VERSION 5.7 ;
  NOWIREEXTENSIONATPIN ON ;
  DIVIDERCHAR "/" ;
  BUSBITCHARS "[]" ;
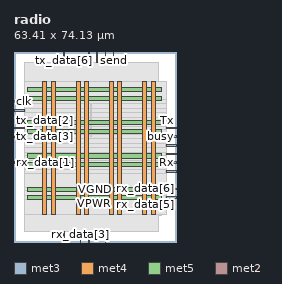
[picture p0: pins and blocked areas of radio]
MACRO radio
  CLASS BLOCK ;
  FOREIGN radio ;
  ORIGIN 0.000 0.000 ;
  SIZE 63.410 BY 74.130 ;
  PIN Rx
    DIRECTION INPUT ;
    USE SIGNAL ;
    ANTENNAGATEAREA 0.196500 ;
    PORT
      LAYER met3 ;
        RECT 59.410 30.640 63.410 31.240 ;
    END
  END Rx
  PIN Tx
    DIRECTION OUTPUT ;
    USE SIGNAL ;
    ANTENNADIFFAREA 0.340600 ;
    PORT
      LAYER met3 ;
        RECT 59.410 44.240 63.410 44.840 ;
    END
  END Tx
  PIN VGND
    DIRECTION INOUT ;
    USE GROUND ;
    PORT
      LAYER met4 ;
        RECT 14.515 10.640 16.115 62.800 ;
    END
    PORT
      LAYER met4 ;
        RECT 27.510 10.640 29.110 62.800 ;
    END
    PORT
      LAYER met4 ;
        RECT 40.505 10.640 42.105 62.800 ;
    END
    PORT
      LAYER met4 ;
        RECT 53.500 10.640 55.100 62.800 ;
    END
    PORT
      LAYER met5 ;
        RECT 5.280 19.840 57.740 21.440 ;
    END
    PORT
      LAYER met5 ;
        RECT 5.280 32.760 57.740 34.360 ;
    END
    PORT
      LAYER met5 ;
        RECT 5.280 45.680 57.740 47.280 ;
    END
    PORT
      LAYER met5 ;
        RECT 5.280 58.600 57.740 60.200 ;
    END
  END VGND
  PIN VPWR
    DIRECTION INOUT ;
    USE POWER ;
    PORT
      LAYER met4 ;
        RECT 11.215 10.640 12.815 62.800 ;
    END
    PORT
      LAYER met4 ;
        RECT 24.210 10.640 25.810 62.800 ;
    END
    PORT
      LAYER met4 ;
        RECT 37.205 10.640 38.805 62.800 ;
    END
    PORT
      LAYER met4 ;
        RECT 50.200 10.640 51.800 62.800 ;
    END
    PORT
      LAYER met5 ;
        RECT 5.280 16.540 57.740 18.140 ;
    END
    PORT
      LAYER met5 ;
        RECT 5.280 29.460 57.740 31.060 ;
    END
    PORT
      LAYER met5 ;
        RECT 5.280 42.380 57.740 43.980 ;
    END
    PORT
      LAYER met5 ;
        RECT 5.280 55.300 57.740 56.900 ;
    END
  END VPWR
  PIN busy
    DIRECTION OUTPUT ;
    USE SIGNAL ;
    ANTENNADIFFAREA 0.340600 ;
    PORT
      LAYER met3 ;
        RECT 59.410 40.840 63.410 41.440 ;
    END
  END busy
  PIN clk
    DIRECTION INPUT ;
    USE SIGNAL ;
    ANTENNAGATEAREA 0.852000 ;
    PORT
      LAYER met3 ;
        RECT 0.000 54.440 4.000 55.040 ;
    END
  END clk
  PIN enable
    DIRECTION INPUT ;
    USE SIGNAL ;
    ANTENNAGATEAREA 0.126000 ;
    PORT
      LAYER met3 ;
        RECT 59.410 34.040 63.410 34.640 ;
    END
  END enable
  PIN receive
    DIRECTION INPUT ;
    USE SIGNAL ;
    ANTENNAGATEAREA 0.196500 ;
    PORT
      LAYER met3 ;
        RECT 59.410 37.440 63.410 38.040 ;
    END
  END receive
  PIN rx_data[0]
    DIRECTION OUTPUT ;
    USE SIGNAL ;
    ANTENNADIFFAREA 0.340600 ;
    PORT
      LAYER met2 ;
        RECT 19.410 0.000 19.690 4.000 ;
    END
  END rx_data[0]
  PIN rx_data[1]
    DIRECTION OUTPUT ;
    USE SIGNAL ;
    ANTENNADIFFAREA 0.340600 ;
    PORT
      LAYER met3 ;
        RECT 0.000 30.640 4.000 31.240 ;
    END
  END rx_data[1]
  PIN rx_data[2]
    DIRECTION OUTPUT ;
    USE SIGNAL ;
    ANTENNADIFFAREA 0.340600 ;
    PORT
      LAYER met2 ;
        RECT 29.070 0.000 29.350 4.000 ;
    END
  END rx_data[2]
  PIN rx_data[3]
    DIRECTION OUTPUT ;
    USE SIGNAL ;
    ANTENNADIFFAREA 0.340600 ;
    PORT
      LAYER met2 ;
        RECT 25.850 0.000 26.130 4.000 ;
    END
  END rx_data[3]
  PIN rx_data[4]
    DIRECTION OUTPUT ;
    USE SIGNAL ;
    ANTENNADIFFAREA 0.340600 ;
    PORT
      LAYER met2 ;
        RECT 35.510 0.000 35.790 4.000 ;
    END
  END rx_data[4]
  PIN rx_data[5]
    DIRECTION OUTPUT ;
    USE SIGNAL ;
    ANTENNADIFFAREA 0.340600 ;
    PORT
      LAYER met3 ;
        RECT 59.410 17.040 63.410 17.640 ;
    END
  END rx_data[5]
  PIN rx_data[6]
    DIRECTION OUTPUT ;
    USE SIGNAL ;
    ANTENNADIFFAREA 0.340600 ;
    PORT
      LAYER met3 ;
        RECT 59.410 20.440 63.410 21.040 ;
    END
  END rx_data[6]
  PIN rx_data[7]
    DIRECTION OUTPUT ;
    USE SIGNAL ;
    ANTENNADIFFAREA 0.340600 ;
    PORT
      LAYER met3 ;
        RECT 59.410 27.240 63.410 27.840 ;
    END
  END rx_data[7]
  PIN send
    DIRECTION INPUT ;
    USE SIGNAL ;
    ANTENNAGATEAREA 0.126000 ;
    PORT
      LAYER met2 ;
        RECT 38.730 70.130 39.010 74.130 ;
    END
  END send
  PIN tx_data[0]
    DIRECTION INPUT ;
    USE SIGNAL ;
    ANTENNAGATEAREA 0.196500 ;
    PORT
      LAYER met2 ;
        RECT 35.510 70.130 35.790 74.130 ;
    END
  END tx_data[0]
  PIN tx_data[1]
    DIRECTION INPUT ;
    USE SIGNAL ;
    ANTENNAGATEAREA 0.196500 ;
    PORT
      LAYER met2 ;
        RECT 32.290 70.130 32.570 74.130 ;
    END
  END tx_data[1]
  PIN tx_data[2]
    DIRECTION INPUT ;
    USE SIGNAL ;
    ANTENNAGATEAREA 0.196500 ;
    PORT
      LAYER met3 ;
        RECT 0.000 44.240 4.000 44.840 ;
    END
  END tx_data[2]
  PIN tx_data[3]
    DIRECTION INPUT ;
    USE SIGNAL ;
    ANTENNAGATEAREA 0.196500 ;
    PORT
      LAYER met3 ;
        RECT 0.000 40.840 4.000 41.440 ;
    END
  END tx_data[3]
  PIN tx_data[4]
    DIRECTION INPUT ;
    USE SIGNAL ;
    ANTENNAGATEAREA 0.196500 ;
    PORT
      LAYER met3 ;
        RECT 0.000 47.640 4.000 48.240 ;
    END
  END tx_data[4]
  PIN tx_data[5]
    DIRECTION INPUT ;
    USE SIGNAL ;
    ANTENNAGATEAREA 0.196500 ;
    PORT
      LAYER met3 ;
        RECT 0.000 51.040 4.000 51.640 ;
    END
  END tx_data[5]
  PIN tx_data[6]
    DIRECTION INPUT ;
    USE SIGNAL ;
    ANTENNAGATEAREA 0.196500 ;
    PORT
      LAYER met2 ;
        RECT 19.410 70.130 19.690 74.130 ;
    END
  END tx_data[6]
  PIN tx_data[7]
    DIRECTION INPUT ;
    USE SIGNAL ;
    ANTENNAGATEAREA 0.196500 ;
    PORT
      LAYER met2 ;
        RECT 29.070 70.130 29.350 74.130 ;
    END
  END tx_data[7]
  OBS
      LAYER nwell ;
        RECT 5.330 10.795 57.690 62.750 ;
      LAYER li1 ;
        RECT 5.520 10.795 57.500 62.645 ;
      LAYER met1 ;
        RECT 4.210 10.240 57.500 62.800 ;
      LAYER met2 ;
        RECT 4.230 69.850 19.130 70.130 ;
        RECT 19.970 69.850 28.790 70.130 ;
        RECT 29.630 69.850 32.010 70.130 ;
        RECT 32.850 69.850 35.230 70.130 ;
        RECT 36.070 69.850 38.450 70.130 ;
        RECT 39.290 69.850 56.480 70.130 ;
        RECT 4.230 4.280 56.480 69.850 ;
        RECT 4.230 4.000 19.130 4.280 ;
        RECT 19.970 4.000 25.570 4.280 ;
        RECT 26.410 4.000 28.790 4.280 ;
        RECT 29.630 4.000 35.230 4.280 ;
        RECT 36.070 4.000 56.480 4.280 ;
      LAYER met3 ;
        RECT 3.990 55.440 59.410 62.725 ;
        RECT 4.400 54.040 59.410 55.440 ;
        RECT 3.990 52.040 59.410 54.040 ;
        RECT 4.400 50.640 59.410 52.040 ;
        RECT 3.990 48.640 59.410 50.640 ;
        RECT 4.400 47.240 59.410 48.640 ;
        RECT 3.990 45.240 59.410 47.240 ;
        RECT 4.400 43.840 59.010 45.240 ;
        RECT 3.990 41.840 59.410 43.840 ;
        RECT 4.400 40.440 59.010 41.840 ;
        RECT 3.990 38.440 59.410 40.440 ;
        RECT 3.990 37.040 59.010 38.440 ;
        RECT 3.990 35.040 59.410 37.040 ;
        RECT 3.990 33.640 59.010 35.040 ;
        RECT 3.990 31.640 59.410 33.640 ;
        RECT 4.400 30.240 59.010 31.640 ;
        RECT 3.990 28.240 59.410 30.240 ;
        RECT 3.990 26.840 59.010 28.240 ;
        RECT 3.990 21.440 59.410 26.840 ;
        RECT 3.990 20.040 59.010 21.440 ;
        RECT 3.990 18.040 59.410 20.040 ;
        RECT 3.990 16.640 59.010 18.040 ;
        RECT 3.990 10.715 59.410 16.640 ;
      LAYER met4 ;
        RECT 29.735 40.975 30.065 53.545 ;
  END
END radio
END LIBRARY

